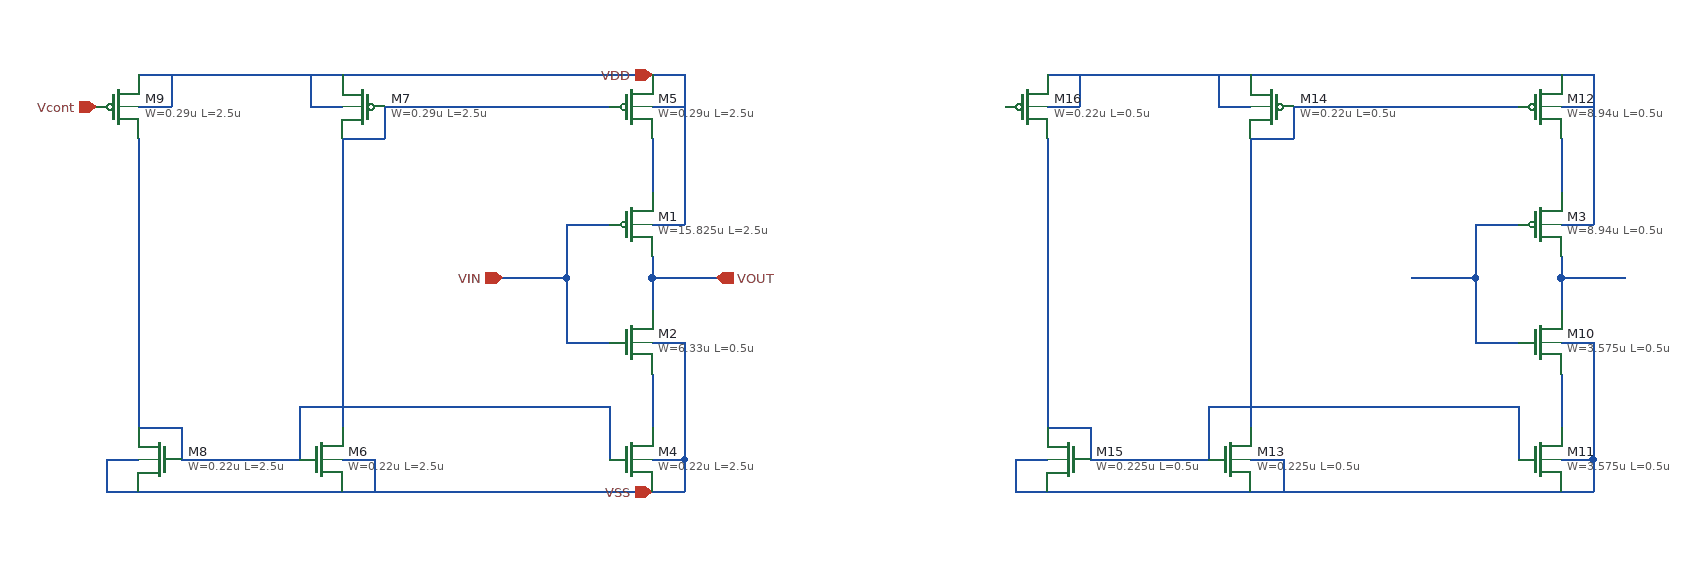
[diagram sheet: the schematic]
v {xschem version=3.4.8RC file_version=1.3}
G {}
K {}
V {}
S {}
F {}
E {}
N -80 -60 -40 -60 { lab=VIN}
N -80 -10 -80 50 { lab=VIN}
N -80 50 -40 50 { lab=VIN}
N 0 -10 0 20 { lab=VOUT}
N 0 -110 0 -90 { lab=#net1}
N -140 -10 -80 -10 { lab=VIN}
N 0 -60 30 -60 { lab=VDD}
N 0 50 30 50 { lab=VSS}
N 30 50 30 100 { lab=VSS}
N 0 80 0 100 { lab=#net2}
N 0 100 0 130 { lab=#net2}
N 0 -10 60 -10 { lab=VOUT}
N -80 -60 -80 -10 { lab=VIN}
N 0 -140 0 -110 { lab=#net1}
N 0 -30 0 -10 { lab=VOUT}
N 30 100 30 160 {lab=VSS}
N 0 160 30 160 {lab=VSS}
N 30 160 30 190 {lab=VSS}
N -0 190 30 190 {lab=VSS}
N 0 -200 30 -200 {lab=VDD}
N -0 -170 30 -170 {lab=VDD}
N -330 110 -40 110 {lab=#net3}
N -330 110 -330 160 {lab=#net3}
N -290 160 -260 160 {lab=VSS}
N -260 160 -260 190 {lab=VSS}
N -290 190 -260 190 {lab=VSS}
N -40 110 -40 150 {lab=#net3}
N -40 150 -40 160 {lab=#net3}
N 30 -200 30 -60 {lab=VDD}
N -320 -170 -290 -170 {lab=VDD}
N -320 -200 -320 -170 {lab=VDD}
N -320 -200 -290 -200 {lab=VDD}
N -290 -140 -250 -140 {lab=#net4}
N -250 -170 -250 -140 {lab=#net4}
N -290 -140 -290 130 {lab=#net4}
N -440 160 -330 160 {lab=#net3}
N -480 130 -440 130 {lab=#net3}
N -440 130 -440 160 {lab=#net3}
N -480 -170 -450 -170 {lab=VDD}
N -450 -200 -450 -170 {lab=VDD}
N -480 -200 -450 -200 {lab=VDD}
N -480 -140 -480 130 {lab=#net3}
N -510 160 -480 160 {lab=VSS}
N -510 160 -510 190 {lab=VSS}
N -510 190 -480 190 {lab=VSS}
N -480 190 10 190 {lab=VSS}
N -480 -200 10 -200 {lab=VDD}
N 770 -60 810 -60 { lab=VIN
spice_ignore=true}
N 770 -10 770 50 { lab=VIN
spice_ignore=true}
N 770 50 810 50 { lab=VIN
spice_ignore=true}
N 850 -10 850 20 { lab=VOUT
spice_ignore=true}
N 850 -110 850 -90 { lab=#net1
spice_ignore=true}
N 710 -10 770 -10 { lab=VIN
spice_ignore=true}
N 850 -60 880 -60 { lab=VDD
spice_ignore=true}
N 850 50 880 50 { lab=VSS
spice_ignore=true}
N 880 50 880 100 { lab=VSS
spice_ignore=true}
N 850 80 850 100 { lab=#net2
spice_ignore=true}
N 850 100 850 130 { lab=#net2
spice_ignore=true}
N 850 -10 910 -10 { lab=VOUT
spice_ignore=true}
N 770 -60 770 -10 { lab=VIN
spice_ignore=true}
N 850 -140 850 -110 { lab=#net1
spice_ignore=true}
N 850 -30 850 -10 { lab=VOUT
spice_ignore=true}
N 880 100 880 160 {lab=VSS
spice_ignore=true}
N 850 160 880 160 {lab=VSS
spice_ignore=true}
N 880 160 880 190 {lab=VSS
spice_ignore=true}
N 850 190 880 190 {lab=VSS
spice_ignore=true}
N 850 -200 880 -200 {lab=VDD
spice_ignore=true}
N 850 -170 880 -170 {lab=VDD
spice_ignore=true}
N 520 110 810 110 {lab=#net3
spice_ignore=true}
N 520 110 520 160 {lab=#net3
spice_ignore=true}
N 560 160 590 160 {lab=VSS
spice_ignore=true}
N 590 160 590 190 {lab=VSS
spice_ignore=true}
N 560 190 590 190 {lab=VSS
spice_ignore=true}
N 810 110 810 150 {lab=#net3
spice_ignore=true}
N 810 150 810 160 {lab=#net3
spice_ignore=true}
N 880 -200 880 -60 {lab=VDD
spice_ignore=true}
N 530 -170 560 -170 {lab=VDD
spice_ignore=true}
N 530 -200 530 -170 {lab=VDD
spice_ignore=true}
N 530 -200 560 -200 {lab=VDD
spice_ignore=true}
N 600 -170 810 -170 {lab=#net4
spice_ignore=true}
N 560 -140 600 -140 {lab=#net4
spice_ignore=true}
N 600 -170 600 -140 {lab=#net4
spice_ignore=true}
N 560 -140 560 130 {lab=#net4
spice_ignore=true}
N 410 160 520 160 {lab=#net3
spice_ignore=true}
N 370 130 410 130 {lab=#net3
spice_ignore=true}
N 410 130 410 160 {lab=#net3
spice_ignore=true}
N 370 -170 400 -170 {lab=VDD
spice_ignore=true}
N 400 -200 400 -170 {lab=VDD
spice_ignore=true}
N 370 -200 400 -200 {lab=VDD
spice_ignore=true}
N 370 -140 370 130 {lab=#net3
spice_ignore=true}
N 340 160 370 160 {lab=VSS
spice_ignore=true}
N 340 160 340 190 {lab=VSS
spice_ignore=true}
N 340 190 370 190 {lab=VSS
spice_ignore=true}
N 370 190 860 190 {lab=VSS
spice_ignore=true}
N 370 -200 860 -200 {lab=VDD
spice_ignore=true}
N -250 -170 -40 -170 {lab=#net4}
C {devices/ipin.sym} -140 -10 0 0 {name=p8 lab=VIN}
C {devices/opin.sym} 60 -10 0 0 {name=p9 lab=VOUT}
C {devices/iopin.sym} 0 -200 3 0 {name=p10 lab=VDD}
C {devices/iopin.sym} 0 190 1 0 {name=p11 lab=VSS}
C {devices/ipin.sym} -520 -170 0 0 {name=p5 lab=Vcont}
C {symbols/pfet_03v3.sym} 830 -60 0 0 {name=M3
L=0.5u
W=8.94u
nf=4
m=1
ad="'int((nf+1)/2) * W/nf * 0.18u'"
pd="'2*int((nf+1)/2) * (W/nf + 0.18u)'"
as="'int((nf+2)/2) * W/nf * 0.18u'"
ps="'2*int((nf+2)/2) * (W/nf + 0.18u)'"
nrd="'0.18u / W'" nrs="'0.18u / W'"
sa=0 sb=0 sd=0
model=pfet_03v3
spiceprefix=X
spice_ignore=true}
C {symbols/nfet_03v3.sym} 830 50 0 0 {name=M10
L=0.5u
W=3.575u
nf=4
m=1
ad="'int((nf+1)/2) * W/nf * 0.18u'"
pd="'2*int((nf+1)/2) * (W/nf + 0.18u)'"
as="'int((nf+2)/2) * W/nf * 0.18u'"
ps="'2*int((nf+2)/2) * (W/nf + 0.18u)'"
nrd="'0.18u / W'" nrs="'0.18u / W'"
sa=0 sb=0 sd=0
model=nfet_03v3
spiceprefix=X
spice_ignore=true}
C {symbols/nfet_03v3.sym} 830 160 0 0 {name=M11
L=0.5u
W=3.575u
nf=4
m=1
ad="'int((nf+1)/2) * W/nf * 0.18u'"
pd="'2*int((nf+1)/2) * (W/nf + 0.18u)'"
as="'int((nf+2)/2) * W/nf * 0.18u'"
ps="'2*int((nf+2)/2) * (W/nf + 0.18u)'"
nrd="'0.18u / W'" nrs="'0.18u / W'"
sa=0 sb=0 sd=0
model=nfet_03v3
spiceprefix=X
spice_ignore=true}
C {symbols/pfet_03v3.sym} 830 -170 0 0 {name=M12
L=0.5u	
W=8.94u
nf=4
m=1
ad="'int((nf+1)/2) * W/nf * 0.18u'"
pd="'2*int((nf+1)/2) * (W/nf + 0.18u)'"
as="'int((nf+2)/2) * W/nf * 0.18u'"
ps="'2*int((nf+2)/2) * (W/nf + 0.18u)'"
nrd="'0.18u / W'" nrs="'0.18u / W'"
sa=0 sb=0 sd=0
model=pfet_03v3
spiceprefix=X
spice_ignore=true}
C {symbols/nfet_03v3.sym} 540 160 0 0 {name=M13
L=0.5u
W=0.225u
nf=1
m=1
ad="'int((nf+1)/2) * W/nf * 0.18u'"
pd="'2*int((nf+1)/2) * (W/nf + 0.18u)'"
as="'int((nf+2)/2) * W/nf * 0.18u'"
ps="'2*int((nf+2)/2) * (W/nf + 0.18u)'"
nrd="'0.18u / W'" nrs="'0.18u / W'"
sa=0 sb=0 sd=0
model=nfet_03v3
spiceprefix=X
spice_ignore=true}
C {symbols/pfet_03v3.sym} 580 -170 0 1 {name=M14
L=0.5u
W=0.22u
nf=1
m=1
ad="'int((nf+1)/2) * W/nf * 0.18u'"
pd="'2*int((nf+1)/2) * (W/nf + 0.18u)'"
as="'int((nf+2)/2) * W/nf * 0.18u'"
ps="'2*int((nf+2)/2) * (W/nf + 0.18u)'"
nrd="'0.18u / W'" nrs="'0.18u / W'"
sa=0 sb=0 sd=0
model=pfet_03v3
spiceprefix=X
spice_ignore=true}
C {symbols/nfet_03v3.sym} 390 160 0 1 {name=M15
L=0.5u
W=0.225u
nf=1
m=1
ad="'int((nf+1)/2) * W/nf * 0.18u'"
pd="'2*int((nf+1)/2) * (W/nf + 0.18u)'"
as="'int((nf+2)/2) * W/nf * 0.18u'"
ps="'2*int((nf+2)/2) * (W/nf + 0.18u)'"
nrd="'0.18u / W'" nrs="'0.18u / W'"
sa=0 sb=0 sd=0
model=nfet_03v3
spiceprefix=X
spice_ignore=true}
C {symbols/pfet_03v3.sym} 350 -170 0 0 {name=M16
L=0.5u
W=0.22u
nf=1
m=1
ad="'int((nf+1)/2) * W/nf * 0.18u'"
pd="'2*int((nf+1)/2) * (W/nf + 0.18u)'"
as="'int((nf+2)/2) * W/nf * 0.18u'"
ps="'2*int((nf+2)/2) * (W/nf + 0.18u)'"
nrd="'0.18u / W'" nrs="'0.18u / W'"
sa=0 sb=0 sd=0
model=pfet_03v3
spiceprefix=X
spice_ignore=true}
C {symbols/nfet_03v3.sym} -20 160 0 0 {name=M4
L=2.5u
W=0.22u
nf=1
m=8
ad="'int((nf+1)/2) * W/nf * 0.18u'"
pd="'2*int((nf+1)/2) * (W/nf + 0.18u)'"
as="'int((nf+2)/2) * W/nf * 0.18u'"
ps="'2*int((nf+2)/2) * (W/nf + 0.18u)'"
nrd="'0.18u / W'" nrs="'0.18u / W'"
sa=0 sb=0 sd=0
model=nfet_03v3
spiceprefix=X
}
C {symbols/pfet_03v3.sym} -20 -170 0 0 {name=M5
L=2.5u	
W=0.29u
nf=1
m=8
ad="'int((nf+1)/2) * W/nf * 0.18u'"
pd="'2*int((nf+1)/2) * (W/nf + 0.18u)'"
as="'int((nf+2)/2) * W/nf * 0.18u'"
ps="'2*int((nf+2)/2) * (W/nf + 0.18u)'"
nrd="'0.18u / W'" nrs="'0.18u / W'"
sa=0 sb=0 sd=0
model=pfet_03v3
spiceprefix=X
}
C {symbols/nfet_03v3.sym} -310 160 0 0 {name=M6
L=2.5u
W=0.22u
nf=1
m=4
ad="'int((nf+1)/2) * W/nf * 0.18u'"
pd="'2*int((nf+1)/2) * (W/nf + 0.18u)'"
as="'int((nf+2)/2) * W/nf * 0.18u'"
ps="'2*int((nf+2)/2) * (W/nf + 0.18u)'"
nrd="'0.18u / W'" nrs="'0.18u / W'"
sa=0 sb=0 sd=0
model=nfet_03v3
spiceprefix=X
}
C {symbols/pfet_03v3.sym} -270 -170 0 1 {name=M7
L=2.5u
W=0.29u
nf=1
m=4
ad="'int((nf+1)/2) * W/nf * 0.18u'"
pd="'2*int((nf+1)/2) * (W/nf + 0.18u)'"
as="'int((nf+2)/2) * W/nf * 0.18u'"
ps="'2*int((nf+2)/2) * (W/nf + 0.18u)'"
nrd="'0.18u / W'" nrs="'0.18u / W'"
sa=0 sb=0 sd=0
model=pfet_03v3
spiceprefix=X
}
C {symbols/nfet_03v3.sym} -460 160 0 1 {name=M8
L=2.5u
W=0.22u
nf=1
m=4
ad="'int((nf+1)/2) * W/nf * 0.18u'"
pd="'2*int((nf+1)/2) * (W/nf + 0.18u)'"
as="'int((nf+2)/2) * W/nf * 0.18u'"
ps="'2*int((nf+2)/2) * (W/nf + 0.18u)'"
nrd="'0.18u / W'" nrs="'0.18u / W'"
sa=0 sb=0 sd=0
model=nfet_03v3
spiceprefix=X
}
C {symbols/pfet_03v3.sym} -500 -170 0 0 {name=M9
L=2.5u
W=0.29u
nf=1
m=4
ad="'int((nf+1)/2) * W/nf * 0.18u'"
pd="'2*int((nf+1)/2) * (W/nf + 0.18u)'"
as="'int((nf+2)/2) * W/nf * 0.18u'"
ps="'2*int((nf+2)/2) * (W/nf + 0.18u)'"
nrd="'0.18u / W'" nrs="'0.18u / W'"
sa=0 sb=0 sd=0
model=pfet_03v3
spiceprefix=X
}
C {symbols/pfet_03v3.sym} -20 -60 0 0 {name=M1
L=2.5u	
W=15.825u
nf=1
m=10
ad="'int((nf+1)/2) * W/nf * 0.18u'"
pd="'2*int((nf+1)/2) * (W/nf + 0.18u)'"
as="'int((nf+2)/2) * W/nf * 0.18u'"
ps="'2*int((nf+2)/2) * (W/nf + 0.18u)'"
nrd="'0.18u / W'" nrs="'0.18u / W'"
sa=0 sb=0 sd=0
model=pfet_03v3
spiceprefix=X
}
C {symbols/nfet_03v3.sym} -20 50 0 0 {name=M2
L=0.5u
W=6.33u
nf=1
m=10
ad="'int((nf+1)/2) * W/nf * 0.18u'"
pd="'2*int((nf+1)/2) * (W/nf + 0.18u)'"
as="'int((nf+2)/2) * W/nf * 0.18u'"
ps="'2*int((nf+2)/2) * (W/nf + 0.18u)'"
nrd="'0.18u / W'" nrs="'0.18u / W'"
sa=0 sb=0 sd=0
model=nfet_03v3
spiceprefix=X
}
